VERSION 5.7 ;
  NOWIREEXTENSIONATPIN ON ;
  DIVIDERCHAR "/" ;
  BUSBITCHARS "[]" ;
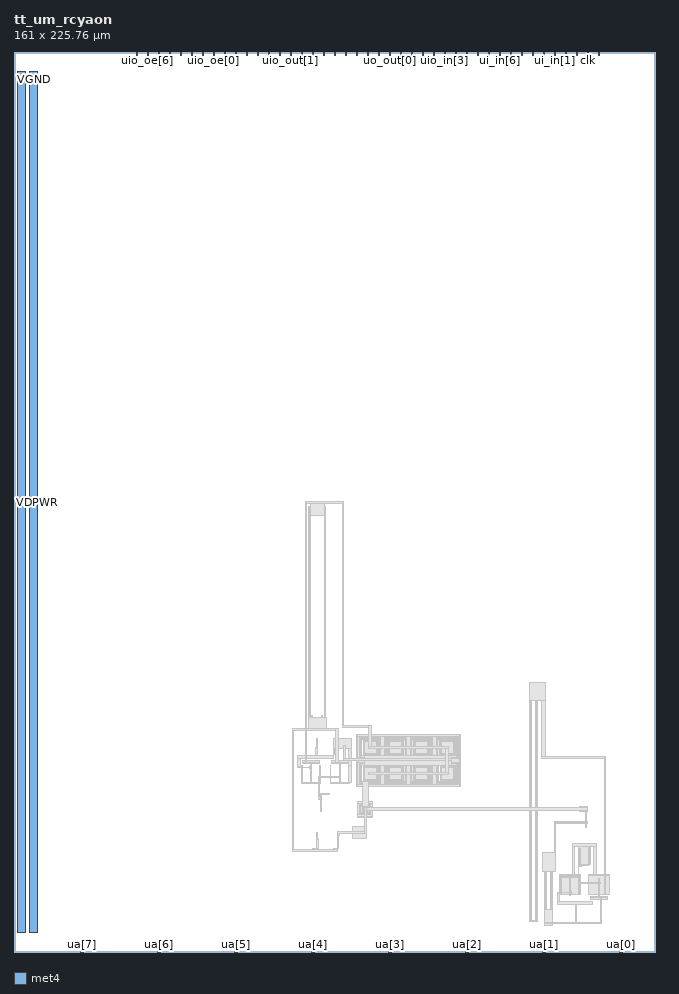
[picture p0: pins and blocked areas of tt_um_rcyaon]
MACRO tt_um_rcyaon
  CLASS BLOCK ;
  FOREIGN tt_um_rcyaon ;
  ORIGIN 0.000 0.000 ;
  SIZE 161.000 BY 225.760 ;
  PIN VGND
    USE GROUND ;
    PORT
      LAYER met4 ;
        RECT 4.000 5.000 6.000 220.760 ;
    END
  END VGND
  PIN VDPWR
    USE POWER ;
    PORT
      LAYER met4 ;
        RECT 1.000 5.000 3.000 220.760 ;
    END
  END VDPWR
  PIN ua[0]
    ANTENNAGATEAREA 16.000000 ;
    ANTENNADIFFAREA 3.180000 ;
    PORT
      LAYER met4 ;
        RECT 151.810 0.000 152.710 1.000 ;
    END
  END ua[0]
  PIN uo_out[7]
    PORT
      LAYER met4 ;
        RECT 74.830 224.760 75.130 225.760 ;
    END
  END uo_out[7]
  PIN uo_out[6]
    PORT
      LAYER met4 ;
        RECT 77.590 224.760 77.890 225.760 ;
    END
  END uo_out[6]
  PIN uo_out[5]
    PORT
      LAYER met4 ;
        RECT 80.350 224.760 80.650 225.760 ;
    END
  END uo_out[5]
  PIN uo_out[4]
    PORT
      LAYER met4 ;
        RECT 83.110 224.760 83.410 225.760 ;
    END
  END uo_out[4]
  PIN uo_out[3]
    PORT
      LAYER met4 ;
        RECT 85.870 224.760 86.170 225.760 ;
    END
  END uo_out[3]
  PIN uo_out[2]
    PORT
      LAYER met4 ;
        RECT 88.630 224.760 88.930 225.760 ;
    END
  END uo_out[2]
  PIN uo_out[1]
    PORT
      LAYER met4 ;
        RECT 91.390 224.760 91.690 225.760 ;
    END
  END uo_out[1]
  PIN uo_out[0]
    PORT
      LAYER met4 ;
        RECT 94.150 224.760 94.450 225.760 ;
    END
  END uo_out[0]
  PIN uio_out[7]
    PORT
      LAYER met4 ;
        RECT 52.750 224.760 53.050 225.760 ;
    END
  END uio_out[7]
  PIN uio_out[6]
    PORT
      LAYER met4 ;
        RECT 55.510 224.760 55.810 225.760 ;
    END
  END uio_out[6]
  PIN uio_out[5]
    PORT
      LAYER met4 ;
        RECT 58.270 224.760 58.570 225.760 ;
    END
  END uio_out[5]
  PIN uio_out[4]
    PORT
      LAYER met4 ;
        RECT 61.030 224.760 61.330 225.760 ;
    END
  END uio_out[4]
  PIN uio_out[3]
    PORT
      LAYER met4 ;
        RECT 63.790 224.760 64.090 225.760 ;
    END
  END uio_out[3]
  PIN uio_out[2]
    PORT
      LAYER met4 ;
        RECT 66.550 224.760 66.850 225.760 ;
    END
  END uio_out[2]
  PIN uio_out[1]
    PORT
      LAYER met4 ;
        RECT 69.310 224.760 69.610 225.760 ;
    END
  END uio_out[1]
  PIN uio_out[0]
    PORT
      LAYER met4 ;
        RECT 72.070 224.760 72.370 225.760 ;
    END
  END uio_out[0]
  PIN uio_oe[7]
    PORT
      LAYER met4 ;
        RECT 30.670 224.760 30.970 225.760 ;
    END
  END uio_oe[7]
  PIN uio_oe[6]
    PORT
      LAYER met4 ;
        RECT 33.430 224.760 33.730 225.760 ;
    END
  END uio_oe[6]
  PIN uio_oe[5]
    PORT
      LAYER met4 ;
        RECT 36.190 224.760 36.490 225.760 ;
    END
  END uio_oe[5]
  PIN uio_oe[4]
    PORT
      LAYER met4 ;
        RECT 38.950 224.760 39.250 225.760 ;
    END
  END uio_oe[4]
  PIN uio_oe[3]
    PORT
      LAYER met4 ;
        RECT 41.710 224.760 42.010 225.760 ;
    END
  END uio_oe[3]
  PIN uio_oe[2]
    PORT
      LAYER met4 ;
        RECT 44.470 224.760 44.770 225.760 ;
    END
  END uio_oe[2]
  PIN uio_oe[1]
    PORT
      LAYER met4 ;
        RECT 47.230 224.760 47.530 225.760 ;
    END
  END uio_oe[1]
  PIN uio_oe[0]
    PORT
      LAYER met4 ;
        RECT 49.990 224.760 50.290 225.760 ;
    END
  END uio_oe[0]
  PIN uio_in[7]
    PORT
      LAYER met4 ;
        RECT 96.910 224.760 97.210 225.760 ;
    END
  END uio_in[7]
  PIN uio_in[6]
    PORT
      LAYER met4 ;
        RECT 99.670 224.760 99.970 225.760 ;
    END
  END uio_in[6]
  PIN uio_in[5]
    PORT
      LAYER met4 ;
        RECT 102.430 224.760 102.730 225.760 ;
    END
  END uio_in[5]
  PIN uio_in[4]
    PORT
      LAYER met4 ;
        RECT 105.190 224.760 105.490 225.760 ;
    END
  END uio_in[4]
  PIN uio_in[3]
    PORT
      LAYER met4 ;
        RECT 107.950 224.760 108.250 225.760 ;
    END
  END uio_in[3]
  PIN uio_in[2]
    PORT
      LAYER met4 ;
        RECT 110.710 224.760 111.010 225.760 ;
    END
  END uio_in[2]
  PIN uio_in[1]
    PORT
      LAYER met4 ;
        RECT 113.470 224.760 113.770 225.760 ;
    END
  END uio_in[1]
  PIN uio_in[0]
    PORT
      LAYER met4 ;
        RECT 116.230 224.760 116.530 225.760 ;
    END
  END uio_in[0]
  PIN ui_in[7]
    PORT
      LAYER met4 ;
        RECT 118.990 224.760 119.290 225.760 ;
    END
  END ui_in[7]
  PIN ui_in[6]
    PORT
      LAYER met4 ;
        RECT 121.750 224.760 122.050 225.760 ;
    END
  END ui_in[6]
  PIN ui_in[5]
    PORT
      LAYER met4 ;
        RECT 124.510 224.760 124.810 225.760 ;
    END
  END ui_in[5]
  PIN ui_in[4]
    PORT
      LAYER met4 ;
        RECT 127.270 224.760 127.570 225.760 ;
    END
  END ui_in[4]
  PIN ui_in[3]
    PORT
      LAYER met4 ;
        RECT 130.030 224.760 130.330 225.760 ;
    END
  END ui_in[3]
  PIN ui_in[2]
    PORT
      LAYER met4 ;
        RECT 132.790 224.760 133.090 225.760 ;
    END
  END ui_in[2]
  PIN ui_in[1]
    PORT
      LAYER met4 ;
        RECT 135.550 224.760 135.850 225.760 ;
    END
  END ui_in[1]
  PIN ui_in[0]
    PORT
      LAYER met4 ;
        RECT 138.310 224.760 138.610 225.760 ;
    END
  END ui_in[0]
  PIN ua[7]
    PORT
      LAYER met4 ;
        RECT 16.570 0.000 17.470 1.000 ;
    END
  END ua[7]
  PIN ua[6]
    PORT
      LAYER met4 ;
        RECT 35.890 0.000 36.790 1.000 ;
    END
  END ua[6]
  PIN ua[5]
    PORT
      LAYER met4 ;
        RECT 55.210 0.000 56.110 1.000 ;
    END
  END ua[5]
  PIN ua[4]
    PORT
      LAYER met4 ;
        RECT 74.530 0.000 75.430 1.000 ;
    END
  END ua[4]
  PIN ua[3]
    PORT
      LAYER met4 ;
        RECT 93.850 0.000 94.750 1.000 ;
    END
  END ua[3]
  PIN ua[2]
    PORT
      LAYER met4 ;
        RECT 113.170 0.000 114.070 1.000 ;
    END
  END ua[2]
  PIN ua[1]
    PORT
      LAYER met4 ;
        RECT 132.490 0.000 133.390 1.000 ;
    END
  END ua[1]
  PIN rst_n
    PORT
      LAYER met4 ;
        RECT 141.070 224.760 141.370 225.760 ;
    END
  END rst_n
  PIN ena
    PORT
      LAYER met4 ;
        RECT 146.590 224.760 146.890 225.760 ;
    END
  END ena
  PIN clk
    PORT
      LAYER met4 ;
        RECT 143.830 224.760 144.130 225.760 ;
    END
  END clk
  OBS
      LAYER pwell ;
        RECT 73.860 111.420 78.260 111.850 ;
        RECT 73.860 56.720 74.290 111.420 ;
        RECT 77.830 56.720 78.260 111.420 ;
        RECT 73.860 56.290 78.260 56.720 ;
        RECT 129.415 65.880 131.325 66.310 ;
        RECT 85.980 53.845 112.000 54.610 ;
        RECT 85.980 48.675 86.745 53.845 ;
        RECT 91.915 48.675 93.185 53.845 ;
        RECT 98.355 48.675 99.625 53.845 ;
        RECT 104.795 48.675 106.065 53.845 ;
        RECT 111.235 48.675 112.000 53.845 ;
        RECT 85.980 47.405 112.000 48.675 ;
        RECT 85.980 42.235 86.745 47.405 ;
        RECT 91.915 42.235 93.185 47.405 ;
        RECT 98.355 42.235 99.625 47.405 ;
        RECT 104.795 42.235 106.065 47.405 ;
        RECT 111.235 42.235 112.000 47.405 ;
        RECT 85.980 41.470 112.000 42.235 ;
        RECT 86.050 36.995 90.030 37.760 ;
        RECT 86.050 34.545 86.815 36.995 ;
        RECT 89.265 34.545 90.030 36.995 ;
        RECT 86.050 33.780 90.030 34.545 ;
        RECT 129.415 8.020 129.845 65.880 ;
        RECT 130.895 8.020 131.325 65.880 ;
        RECT 129.415 7.590 131.325 8.020 ;
        RECT 133.145 22.890 135.055 23.320 ;
        RECT 133.145 8.030 133.575 22.890 ;
        RECT 134.625 8.030 135.055 22.890 ;
      LAYER nwell ;
        RECT 141.675 21.870 144.565 26.860 ;
        RECT 136.950 14.310 142.120 19.540 ;
        RECT 144.175 14.310 149.345 19.540 ;
      LAYER pwell ;
        RECT 133.145 7.600 135.055 8.030 ;
      LAYER li1 ;
        RECT 73.990 111.550 78.130 111.720 ;
        RECT 73.990 56.590 74.160 111.550 ;
        RECT 74.640 57.070 74.990 59.230 ;
        RECT 77.130 57.070 77.480 59.230 ;
        RECT 77.960 56.590 78.130 111.550 ;
        RECT 73.990 56.420 78.130 56.590 ;
        RECT 129.545 66.010 131.195 66.180 ;
        RECT 86.110 53.985 111.870 54.480 ;
        RECT 75.820 49.520 75.990 53.520 ;
        RECT 80.130 49.520 80.300 53.520 ;
        RECT 73.765 49.080 75.765 49.310 ;
        RECT 78.075 49.080 80.075 49.310 ;
        RECT 86.110 48.535 86.605 53.985 ;
        RECT 86.925 53.305 91.735 53.665 ;
        RECT 86.925 49.215 87.285 53.305 ;
        RECT 87.595 49.525 91.065 52.995 ;
        RECT 91.375 49.215 91.735 53.305 ;
        RECT 86.925 48.855 91.735 49.215 ;
        RECT 92.055 48.535 93.045 53.985 ;
        RECT 93.365 53.305 98.175 53.665 ;
        RECT 93.365 49.215 93.725 53.305 ;
        RECT 94.035 49.525 97.505 52.995 ;
        RECT 97.815 49.215 98.175 53.305 ;
        RECT 93.365 48.855 98.175 49.215 ;
        RECT 98.495 48.535 99.485 53.985 ;
        RECT 99.805 53.305 104.615 53.665 ;
        RECT 99.805 49.215 100.165 53.305 ;
        RECT 100.475 49.525 103.945 52.995 ;
        RECT 104.255 49.215 104.615 53.305 ;
        RECT 99.805 48.855 104.615 49.215 ;
        RECT 104.935 48.535 105.925 53.985 ;
        RECT 106.245 53.305 111.055 53.665 ;
        RECT 106.245 49.215 106.605 53.305 ;
        RECT 106.915 49.525 110.385 52.995 ;
        RECT 110.695 49.215 111.055 53.305 ;
        RECT 106.245 48.855 111.055 49.215 ;
        RECT 111.375 48.535 111.870 53.985 ;
        RECT 72.310 47.390 76.590 47.620 ;
        RECT 79.535 47.390 83.815 47.620 ;
        RECT 86.110 47.545 111.870 48.535 ;
        RECT 72.085 42.780 72.255 46.780 ;
        RECT 74.365 42.780 74.535 46.780 ;
        RECT 76.645 42.780 76.815 46.780 ;
        RECT 79.310 42.780 79.480 46.780 ;
        RECT 81.590 42.780 81.760 46.780 ;
        RECT 83.870 42.780 84.040 46.780 ;
        RECT 86.110 42.095 86.605 47.545 ;
        RECT 86.925 46.865 91.735 47.225 ;
        RECT 86.925 42.775 87.285 46.865 ;
        RECT 87.595 43.085 91.065 46.555 ;
        RECT 91.375 42.775 91.735 46.865 ;
        RECT 86.925 42.415 91.735 42.775 ;
        RECT 92.055 42.095 93.045 47.545 ;
        RECT 93.365 46.865 98.175 47.225 ;
        RECT 93.365 42.775 93.725 46.865 ;
        RECT 94.035 43.085 97.505 46.555 ;
        RECT 97.815 42.775 98.175 46.865 ;
        RECT 93.365 42.415 98.175 42.775 ;
        RECT 98.495 42.095 99.485 47.545 ;
        RECT 99.805 46.865 104.615 47.225 ;
        RECT 99.805 42.775 100.165 46.865 ;
        RECT 100.475 43.085 103.945 46.555 ;
        RECT 104.255 42.775 104.615 46.865 ;
        RECT 99.805 42.415 104.615 42.775 ;
        RECT 104.935 42.095 105.925 47.545 ;
        RECT 106.245 46.865 111.055 47.225 ;
        RECT 106.245 42.775 106.605 46.865 ;
        RECT 106.915 43.085 110.385 46.555 ;
        RECT 110.695 42.775 111.055 46.865 ;
        RECT 106.245 42.415 111.055 42.775 ;
        RECT 111.375 42.095 111.870 47.545 ;
        RECT 86.110 41.600 111.870 42.095 ;
        RECT 77.035 39.430 79.035 39.660 ;
        RECT 76.810 35.220 76.980 39.220 ;
        RECT 86.180 37.125 89.900 37.630 ;
        RECT 86.180 34.415 86.685 37.125 ;
        RECT 86.995 36.455 89.085 36.815 ;
        RECT 86.995 35.085 87.355 36.455 ;
        RECT 87.645 35.375 88.435 36.165 ;
        RECT 88.725 35.085 89.085 36.455 ;
        RECT 86.995 34.725 89.085 35.085 ;
        RECT 89.395 34.415 89.900 37.125 ;
        RECT 86.180 33.910 89.900 34.415 ;
        RECT 75.995 26.035 76.165 30.035 ;
        RECT 81.185 26.040 81.355 30.040 ;
        RECT 74.940 25.595 75.940 25.825 ;
        RECT 80.130 25.600 81.130 25.830 ;
        RECT 129.545 7.890 129.715 66.010 ;
        RECT 130.195 63.370 130.545 65.530 ;
        RECT 131.025 7.890 131.195 66.010 ;
        RECT 142.395 35.325 143.395 35.555 ;
        RECT 143.450 31.115 143.620 35.115 ;
        RECT 141.865 26.400 144.375 26.670 ;
        RECT 129.545 7.720 131.195 7.890 ;
        RECT 133.275 23.020 134.925 23.190 ;
        RECT 133.275 7.900 133.445 23.020 ;
        RECT 133.925 20.380 134.275 22.540 ;
        RECT 133.925 8.380 134.275 10.540 ;
        RECT 134.755 7.900 134.925 23.020 ;
        RECT 141.895 22.050 142.065 26.050 ;
        RECT 144.175 22.050 144.345 26.050 ;
        RECT 142.120 21.610 144.120 21.840 ;
        RECT 137.140 19.080 141.930 19.350 ;
        RECT 144.365 19.080 149.155 19.350 ;
        RECT 137.170 14.490 137.340 18.490 ;
        RECT 139.450 14.490 139.620 18.490 ;
        RECT 141.730 14.490 141.900 18.490 ;
        RECT 146.675 14.490 146.845 18.490 ;
        RECT 144.620 13.650 148.900 13.880 ;
        RECT 138.850 11.960 140.850 12.190 ;
        RECT 143.160 11.960 145.160 12.190 ;
        RECT 133.275 7.730 134.925 7.900 ;
        RECT 140.905 7.750 141.075 11.750 ;
      LAYER met1 ;
        RECT 73.010 113.020 82.720 113.040 ;
        RECT 73.010 112.480 82.760 113.020 ;
        RECT 74.290 109.460 77.810 112.480 ;
        RECT 74.690 58.730 74.940 59.205 ;
        RECT 77.180 58.730 77.430 59.205 ;
        RECT 73.760 56.160 78.510 58.730 ;
        RECT 82.360 56.760 82.760 112.480 ;
        RECT 129.425 67.530 132.865 67.560 ;
        RECT 129.425 63.135 133.215 67.530 ;
        RECT 82.345 56.260 89.585 56.760 ;
        RECT 69.780 55.450 81.390 56.160 ;
        RECT 69.790 25.820 70.170 55.450 ;
        RECT 93.390 53.670 98.180 53.680 ;
        RECT 99.830 53.670 104.620 53.680 ;
        RECT 80.170 53.520 84.550 53.650 ;
        RECT 75.790 51.340 76.020 53.520 ;
        RECT 75.750 49.330 76.035 51.340 ;
        RECT 80.100 51.135 84.550 53.520 ;
        RECT 80.100 49.520 80.330 51.135 ;
        RECT 73.765 49.325 76.035 49.330 ;
        RECT 78.075 49.325 80.075 49.330 ;
        RECT 71.160 48.655 80.085 49.325 ;
        RECT 71.160 46.220 71.805 48.655 ;
        RECT 72.320 47.640 76.560 48.040 ;
        RECT 79.555 47.640 83.795 48.040 ;
        RECT 72.310 47.370 76.590 47.640 ;
        RECT 79.535 47.370 83.815 47.640 ;
        RECT 72.055 42.610 72.285 46.780 ;
        RECT 74.335 46.605 74.565 47.180 ;
        RECT 74.175 46.010 74.750 46.605 ;
        RECT 74.335 42.780 74.565 46.010 ;
        RECT 76.615 44.115 76.845 46.780 ;
        RECT 76.430 43.755 77.005 44.115 ;
        RECT 76.615 42.610 76.845 43.755 ;
        RECT 72.055 42.380 76.845 42.610 ;
        RECT 79.280 42.610 79.510 46.780 ;
        RECT 81.560 44.115 81.790 47.180 ;
        RECT 83.975 46.780 84.550 51.135 ;
        RECT 86.930 53.290 91.740 53.670 ;
        RECT 93.380 53.300 98.180 53.670 ;
        RECT 99.820 53.300 104.620 53.670 ;
        RECT 106.260 53.300 111.050 53.680 ;
        RECT 86.930 49.240 87.270 53.290 ;
        RECT 87.805 49.735 90.855 52.785 ;
        RECT 91.390 49.240 91.730 53.290 ;
        RECT 93.380 49.240 93.720 53.300 ;
        RECT 94.245 49.735 97.295 52.785 ;
        RECT 97.810 49.240 98.150 53.300 ;
        RECT 86.930 48.870 91.740 49.240 ;
        RECT 93.380 48.870 98.180 49.240 ;
        RECT 99.820 49.230 100.160 53.300 ;
        RECT 100.685 49.735 103.735 52.785 ;
        RECT 104.260 49.230 104.600 53.300 ;
        RECT 106.270 49.230 106.610 53.300 ;
        RECT 107.125 49.735 110.175 52.785 ;
        RECT 110.710 49.230 111.050 53.300 ;
        RECT 99.820 48.870 104.620 49.230 ;
        RECT 86.950 48.860 91.740 48.870 ;
        RECT 93.390 48.860 98.180 48.870 ;
        RECT 88.380 48.830 88.640 48.860 ;
        RECT 99.830 48.850 104.620 48.870 ;
        RECT 106.240 48.870 111.050 49.230 ;
        RECT 132.245 48.970 133.215 63.135 ;
        RECT 106.240 48.850 111.030 48.870 ;
        RECT 132.240 48.570 148.440 48.970 ;
        RECT 132.245 48.550 133.215 48.570 ;
        RECT 81.395 43.755 81.970 44.115 ;
        RECT 81.560 42.780 81.790 43.755 ;
        RECT 83.840 42.610 84.550 46.780 ;
        RECT 79.280 42.430 84.550 42.610 ;
        RECT 86.930 47.220 91.720 47.240 ;
        RECT 93.390 47.220 98.180 47.240 ;
        RECT 99.830 47.220 104.620 47.240 ;
        RECT 86.930 46.860 91.730 47.220 ;
        RECT 86.930 42.780 87.270 46.860 ;
        RECT 87.805 43.295 90.855 46.345 ;
        RECT 91.390 42.780 91.730 46.860 ;
        RECT 79.280 42.380 84.070 42.430 ;
        RECT 86.930 42.420 91.730 42.780 ;
        RECT 93.380 46.860 98.180 47.220 ;
        RECT 99.820 46.860 104.620 47.220 ;
        RECT 106.260 47.210 106.600 47.220 ;
        RECT 110.710 47.210 111.050 47.220 ;
        RECT 93.380 42.780 93.720 46.860 ;
        RECT 94.245 43.295 97.295 46.345 ;
        RECT 97.810 42.780 98.150 46.860 ;
        RECT 99.820 42.780 100.160 46.860 ;
        RECT 100.685 43.295 103.735 46.345 ;
        RECT 104.260 42.780 104.600 46.860 ;
        RECT 106.240 46.830 111.050 47.210 ;
        RECT 106.260 42.780 106.600 46.830 ;
        RECT 107.125 43.295 110.175 46.345 ;
        RECT 110.710 42.780 111.050 46.830 ;
        RECT 93.380 42.420 98.180 42.780 ;
        RECT 86.930 42.400 91.720 42.420 ;
        RECT 93.390 42.400 98.180 42.420 ;
        RECT 99.780 42.420 104.600 42.780 ;
        RECT 106.240 42.420 111.050 42.780 ;
        RECT 99.780 42.400 104.570 42.420 ;
        RECT 106.240 42.400 111.030 42.420 ;
        RECT 76.435 39.680 77.280 39.725 ;
        RECT 76.435 39.410 79.035 39.680 ;
        RECT 76.435 39.390 77.280 39.410 ;
        RECT 76.435 39.220 76.980 39.390 ;
        RECT 76.435 38.300 77.010 39.220 ;
        RECT 76.780 35.220 77.010 38.300 ;
        RECT 87.960 36.810 88.220 36.830 ;
        RECT 87.020 36.800 89.070 36.810 ;
        RECT 87.010 36.460 89.070 36.800 ;
        RECT 87.010 35.090 87.350 36.460 ;
        RECT 87.625 35.355 88.455 36.185 ;
        RECT 88.730 35.090 89.070 36.460 ;
        RECT 141.925 35.300 143.845 36.420 ;
        RECT 87.010 34.740 89.070 35.090 ;
        RECT 87.020 34.710 89.070 34.740 ;
        RECT 143.420 32.810 143.650 35.115 ;
        RECT 143.420 32.680 143.805 32.810 ;
        RECT 81.190 30.045 81.545 30.165 ;
        RECT 81.190 30.040 81.555 30.045 ;
        RECT 75.965 28.220 76.195 30.035 ;
        RECT 81.155 29.725 81.555 30.040 ;
        RECT 81.155 29.315 81.545 29.725 ;
        RECT 75.965 26.035 76.485 28.220 ;
        RECT 81.155 26.040 81.385 29.315 ;
        RECT 84.870 28.400 88.440 31.550 ;
        RECT 74.940 25.820 75.940 25.845 ;
        RECT 76.115 25.820 76.485 26.035 ;
        RECT 80.130 25.820 81.130 25.850 ;
        RECT 69.790 25.180 81.190 25.820 ;
        RECT 69.795 25.170 81.190 25.180 ;
        RECT 135.625 24.970 135.915 32.675 ;
        RECT 143.420 32.360 143.845 32.680 ;
        RECT 143.420 32.125 143.805 32.360 ;
        RECT 143.420 31.115 143.650 32.125 ;
        RECT 132.580 20.230 135.915 24.970 ;
        RECT 140.005 26.400 146.095 27.315 ;
        RECT 140.005 19.350 140.670 26.400 ;
        RECT 141.865 22.970 142.095 26.050 ;
        RECT 144.135 25.820 144.410 26.400 ;
        RECT 141.520 22.050 142.095 22.970 ;
        RECT 144.145 22.050 144.375 25.820 ;
        RECT 141.520 21.880 142.065 22.050 ;
        RECT 141.520 21.860 142.365 21.880 ;
        RECT 141.520 21.590 144.120 21.860 ;
        RECT 141.520 21.545 142.365 21.590 ;
        RECT 145.405 19.350 146.070 26.400 ;
        RECT 137.140 19.080 141.930 19.350 ;
        RECT 144.365 19.080 149.155 19.350 ;
        RECT 137.140 18.660 141.930 18.890 ;
        RECT 136.245 12.615 136.890 15.050 ;
        RECT 137.140 14.490 137.370 18.660 ;
        RECT 139.420 15.260 139.650 18.490 ;
        RECT 141.700 17.515 141.930 18.660 ;
        RECT 146.645 17.515 146.875 18.490 ;
        RECT 141.515 17.155 142.090 17.515 ;
        RECT 146.480 17.155 147.055 17.515 ;
        RECT 139.260 14.665 139.835 15.260 ;
        RECT 139.420 14.090 139.650 14.665 ;
        RECT 141.700 14.490 141.930 17.155 ;
        RECT 146.645 14.090 146.875 17.155 ;
        RECT 148.160 14.730 148.420 15.050 ;
        RECT 144.620 13.630 148.900 13.900 ;
        RECT 144.640 13.230 148.880 13.630 ;
        RECT 136.245 11.945 145.170 12.615 ;
        RECT 138.850 11.940 141.120 11.945 ;
        RECT 143.160 11.940 145.160 11.945 ;
        RECT 133.030 6.590 135.110 10.700 ;
        RECT 140.835 9.930 141.120 11.940 ;
        RECT 140.875 7.750 141.105 9.930 ;
      LAYER met2 ;
        RECT 89.090 56.335 89.370 56.705 ;
        RECT 80.770 47.540 81.390 56.170 ;
        RECT 82.600 48.570 83.130 51.760 ;
        RECT 89.160 51.005 89.440 51.375 ;
        RECT 95.530 50.985 95.810 51.355 ;
        RECT 101.930 50.955 102.210 51.325 ;
        RECT 108.410 51.005 108.690 51.375 ;
        RECT 88.030 48.570 109.720 49.240 ;
        RECT 82.600 47.990 109.720 48.570 ;
        RECT 82.610 47.970 109.720 47.990 ;
        RECT 88.030 46.850 109.720 47.970 ;
        RECT 71.340 46.370 71.600 46.585 ;
        RECT 74.380 46.370 74.640 46.430 ;
        RECT 71.160 46.225 74.750 46.370 ;
        RECT 74.380 46.110 74.640 46.225 ;
        RECT 89.250 44.635 89.530 45.005 ;
        RECT 95.630 44.675 95.910 45.045 ;
        RECT 102.180 44.635 102.460 45.005 ;
        RECT 108.370 44.675 108.650 45.045 ;
        RECT 76.435 44.095 76.590 44.100 ;
        RECT 76.435 44.035 76.755 44.095 ;
        RECT 81.505 44.035 81.765 44.115 ;
        RECT 76.435 43.890 81.825 44.035 ;
        RECT 76.435 43.775 76.755 43.890 ;
        RECT 81.505 43.795 81.765 43.890 ;
        RECT 76.435 38.950 76.590 43.775 ;
        RECT 76.435 38.630 76.765 38.950 ;
        RECT 76.435 38.300 76.590 38.630 ;
        RECT 87.390 36.510 88.860 42.830 ;
        RECT 87.960 35.420 143.850 36.150 ;
        RECT 143.585 32.650 143.845 32.680 ;
        RECT 135.585 32.360 143.845 32.650 ;
        RECT 135.585 32.275 143.795 32.360 ;
        RECT 135.645 32.270 135.905 32.275 ;
        RECT 81.265 29.675 88.455 30.115 ;
        RECT 141.520 22.640 141.675 22.970 ;
        RECT 141.520 22.320 141.850 22.640 ;
        RECT 141.520 17.495 141.675 22.320 ;
        RECT 141.520 17.380 141.840 17.495 ;
        RECT 146.590 17.380 146.850 17.475 ;
        RECT 141.520 17.235 146.910 17.380 ;
        RECT 141.520 17.175 141.840 17.235 ;
        RECT 141.520 17.170 141.675 17.175 ;
        RECT 146.590 17.155 146.850 17.235 ;
        RECT 139.465 15.045 139.725 15.160 ;
        RECT 136.245 14.900 139.835 15.045 ;
        RECT 136.425 14.685 136.685 14.900 ;
        RECT 139.465 14.840 139.725 14.900 ;
        RECT 148.115 14.780 148.465 49.000 ;
        RECT 148.160 14.730 148.420 14.780 ;
        RECT 147.010 7.490 147.310 13.770 ;
        RECT 133.180 7.110 147.310 7.490 ;
      LAYER met3 ;
        RECT 73.000 47.660 73.360 113.010 ;
        RECT 89.000 51.490 89.560 56.750 ;
        RECT 89.000 50.930 108.970 51.490 ;
        RECT 108.210 45.140 108.920 50.930 ;
        RECT 89.020 44.580 108.970 45.140 ;
        RECT 87.950 29.660 88.420 36.140 ;
  END
END tt_um_rcyaon
END LIBRARY

